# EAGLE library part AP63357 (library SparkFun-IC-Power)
The AP63356/AP63357 is a 3.5A, synchronous buck converter with a wide input voltage range of 3.8V to 32V. The device fully integrates a 74mΩ high-side power MOSFET and a 40mΩ low-side power MOSFET to provide high-efficiency step-down DC-DC conversion.

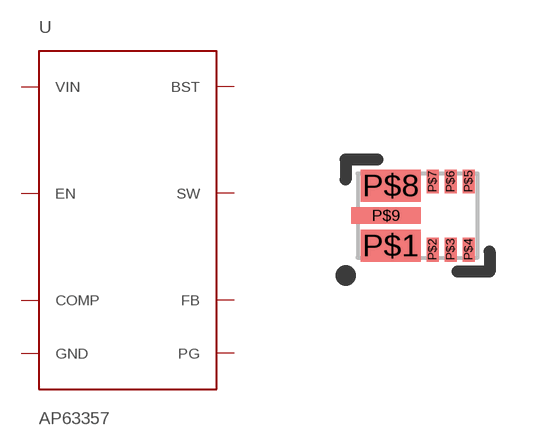
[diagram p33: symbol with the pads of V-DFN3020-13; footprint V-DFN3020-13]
Designator prefix U

## AP63357 (PN: AP63357DV-7; PROD_ID: VREG-17224; VALUE: AP63357)  [V-DFN3020-13]
P$1  VIN  pwr
P$2  EN
P$3  FB  in
P$4  COMP
P$5  PG  out
P$6  BST
P$7  SW  pwr
P$8  GND  sup
P$9  SW  pwr

## Footprint V-DFN3020-13 (pad centres in mm)
smd 1.5 x 0.8: P$1 -0.675,-0.75; P$8 -0.675,0.75
smd 0.3 x 0.6: P$2 0.375,-0.85; P$3 0.825,-0.85; P$4 1.275,-0.85; P$5 1.275,0.85; P$6 0.825,0.85; P$7 0.375,0.85
smd 1.73 x 0.4: P$9 -0.79,0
